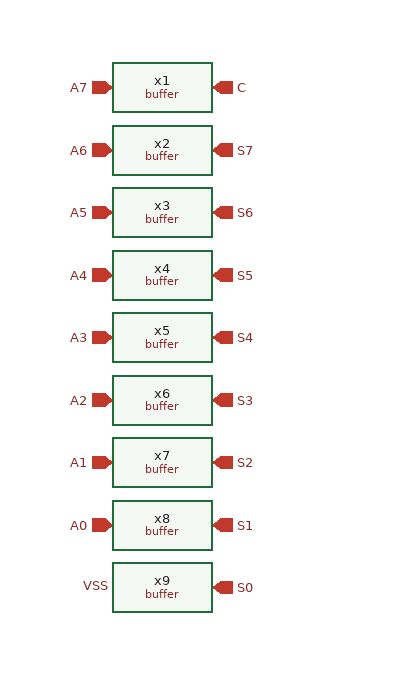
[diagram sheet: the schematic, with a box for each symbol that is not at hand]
v {xschem version=3.4.6 file_version=1.2}
G {}
K {}
V {}
S {}
E {}
C {devices/ipin.sym} -170 30 0 0 {name=p5 lab=A7}
C {devices/opin.sym} -90 80 0 0 {name=p6 lab=S7}
C {devices/ipin.sym} -170 80 0 0 {name=p7 lab=A6}
C {devices/ipin.sym} -170 130 0 0 {name=p8 lab=A5}
C {devices/ipin.sym} -170 180 0 0 {name=p9 lab=A4}
C {devices/ipin.sym} -170 230 0 0 {name=p10 lab=A3}
C {devices/ipin.sym} -170 280 0 0 {name=p11 lab=A2}
C {devices/ipin.sym} -170 330 0 0 {name=p12 lab=A1}
C {devices/ipin.sym} -170 380 0 0 {name=p13 lab=A0}
C {devices/opin.sym} -90 130 0 0 {name=p14 lab=S6}
C {devices/opin.sym} -90 180 0 0 {name=p15 lab=S5}
C {devices/opin.sym} -90 230 0 0 {name=p16 lab=S4}
C {devices/opin.sym} -90 280 0 0 {name=p17 lab=S3}
C {devices/opin.sym} -90 330 0 0 {name=p18 lab=S2}
C {devices/opin.sym} -90 380 0 0 {name=p19 lab=S1}
C {devices/opin.sym} -90 30 0 0 {name=p20 lab=C}
C {INV/buffer.sym} -130 30 0 0 {name=x1 VSS=VSS VDD=VDD}
C {INV/buffer.sym} -130 80 0 0 {name=x2 VSS=VSS VDD=VDD}
C {INV/buffer.sym} -130 130 0 0 {name=x3 VSS=VSS VDD=VDD}
C {INV/buffer.sym} -130 180 0 0 {name=x4 VSS=VSS VDD=VDD}
C {INV/buffer.sym} -130 230 0 0 {name=x5 VSS=VSS VDD=VDD}
C {INV/buffer.sym} -130 280 0 0 {name=x6 VSS=VSS VDD=VDD}
C {INV/buffer.sym} -130 330 0 0 {name=x7 VSS=VSS VDD=VDD}
C {INV/buffer.sym} -130 380 0 0 {name=x8 VSS=VSS VDD=VDD}
C {devices/opin.sym} -90 430 0 0 {name=p21 lab=S0}
C {INV/buffer.sym} -130 430 0 0 {name=x9 VSS=VSS VDD=VDD}
C {devices/lab_pin.sym} -170 430 0 0 {name=p22 lab=VSS}
